One B-rep face of a CAD part: STEP entity #1211.
In plain terms, the planar face has unit normal (-1, 0, 0).
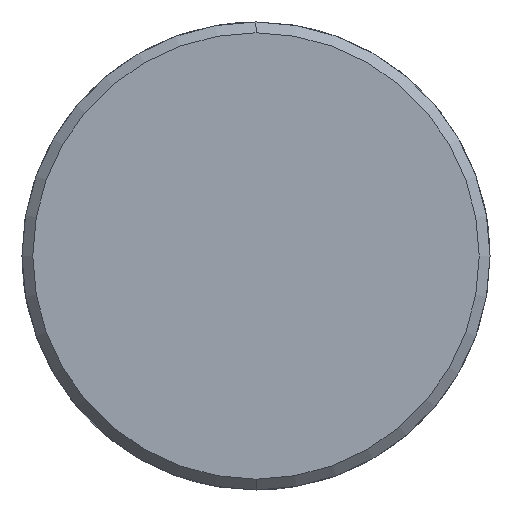
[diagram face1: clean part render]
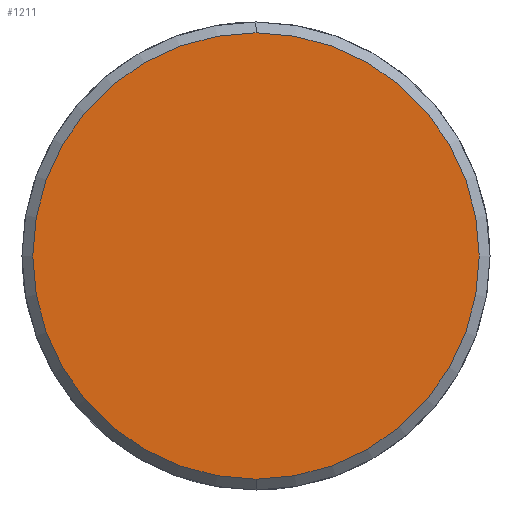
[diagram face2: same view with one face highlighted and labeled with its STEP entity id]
Its self-contained STEP definition (entity closure, numbers rounded to 3 decimals):
#1143=CARTESIAN_POINT('Vertex',(-10.,0.,-31.)) ;
#1146=CARTESIAN_POINT('Axis2P3D Location',(-10.,0.,0.)) ;
#1150=CARTESIAN_POINT('Vertex',(-10.,31.,0.)) ;
#1153=CARTESIAN_POINT('Axis2P3D Location',(-10.,0.,0.)) ;
#1157=CARTESIAN_POINT('Vertex',(-10.,0.,31.)) ;
#1179=CARTESIAN_POINT('Axis2P3D Location',(-10.,0.,0.)) ;
#1183=CARTESIAN_POINT('Vertex',(-10.,-31.,0.)) ;
#1186=CARTESIAN_POINT('Axis2P3D Location',(-10.,0.,0.)) ;
#1200=CARTESIAN_POINT('Axis2P3D Location',(-10.,0.,0.)) ;
#1147=DIRECTION('Axis2P3D Direction',(1.,0.,-0.)) ;
#1154=DIRECTION('Axis2P3D Direction',(1.,0.,-0.)) ;
#1180=DIRECTION('Axis2P3D Direction',(1.,0.,-0.)) ;
#1187=DIRECTION('Axis2P3D Direction',(1.,0.,-0.)) ;
#1201=DIRECTION('Axis2P3D Direction',(1.,0.,-0.)) ;
#1202=DIRECTION('Axis2P3D XDirection',(-0.,0.,-1.)) ;
#1148=AXIS2_PLACEMENT_3D('Circle Axis2P3D',#1146,#1147,$) ;
#1155=AXIS2_PLACEMENT_3D('Circle Axis2P3D',#1153,#1154,$) ;
#1181=AXIS2_PLACEMENT_3D('Circle Axis2P3D',#1179,#1180,$) ;
#1188=AXIS2_PLACEMENT_3D('Circle Axis2P3D',#1186,#1187,$) ;
#1203=AXIS2_PLACEMENT_3D('Plane Axis2P3D',#1200,#1201,#1202) ;
#1206=ORIENTED_EDGE('',*,*,#1152,.F.) ;
#1207=ORIENTED_EDGE('',*,*,#1190,.F.) ;
#1208=ORIENTED_EDGE('',*,*,#1185,.F.) ;
#1209=ORIENTED_EDGE('',*,*,#1159,.F.) ;
#1211=ADVANCED_FACE('351-50X126X240',(#1210),#1204,.F.) ;
#1149=CIRCLE('generated circle',#1148,31.) ;
#1156=CIRCLE('generated circle',#1155,31.) ;
#1182=CIRCLE('generated circle',#1181,31.) ;
#1189=CIRCLE('generated circle',#1188,31.) ;
#1152=EDGE_CURVE('',#1144,#1151,#1149,.T.) ;
#1159=EDGE_CURVE('',#1151,#1158,#1156,.T.) ;
#1185=EDGE_CURVE('',#1158,#1184,#1182,.T.) ;
#1190=EDGE_CURVE('',#1184,#1144,#1189,.T.) ;
#1205=EDGE_LOOP('',(#1206,#1207,#1208,#1209)) ;
#1210=FACE_OUTER_BOUND('',#1205,.T.) ;
#1204=PLANE('Plane',#1203) ;
#1144=VERTEX_POINT('',#1143) ;
#1151=VERTEX_POINT('',#1150) ;
#1158=VERTEX_POINT('',#1157) ;
#1184=VERTEX_POINT('',#1183) ;
